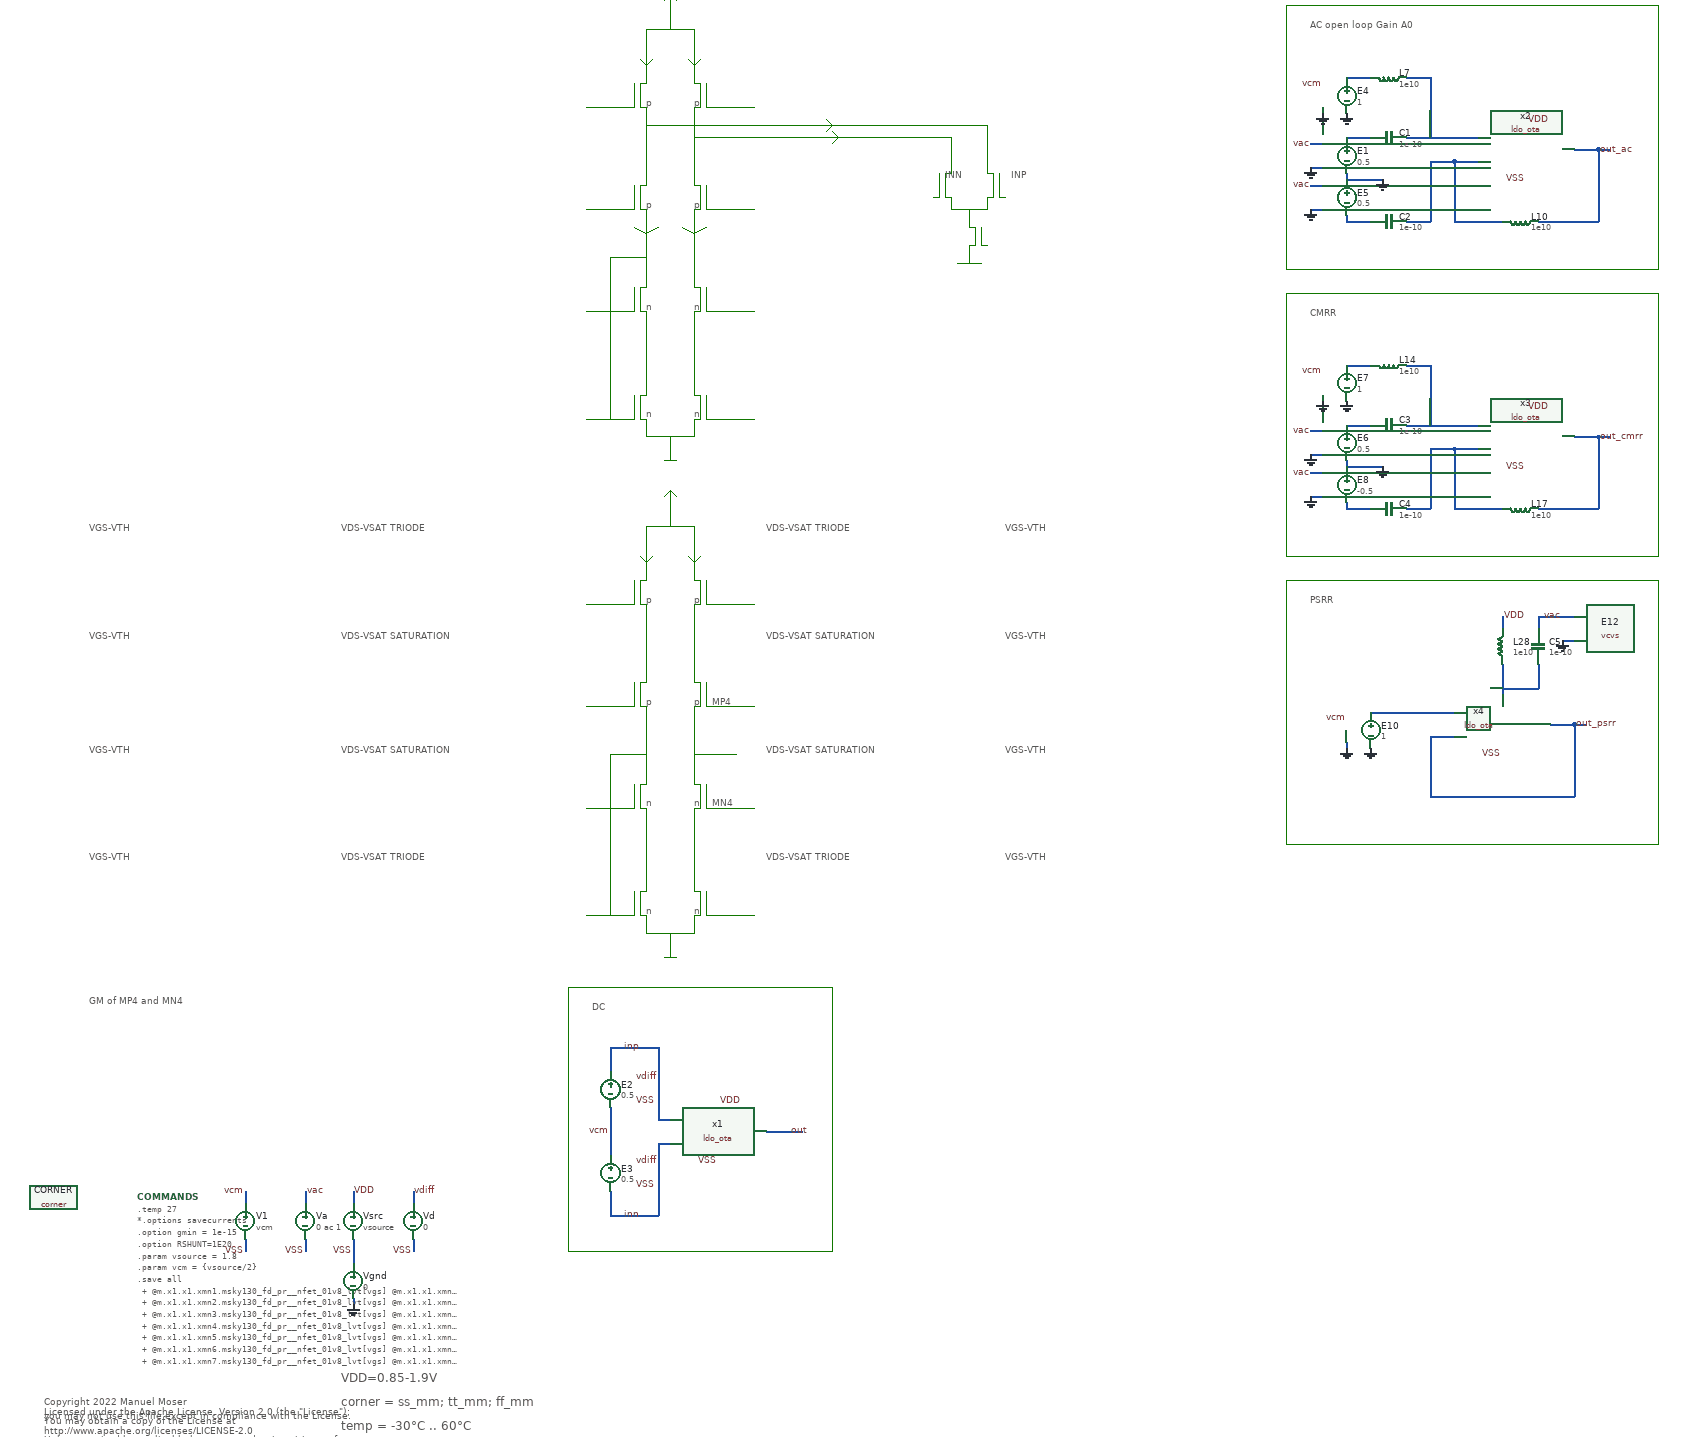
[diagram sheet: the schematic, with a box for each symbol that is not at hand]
v {xschem version=3.1.0 file_version=1.2
}
G {}
K {}
V {}
S {}
E {}
L 4 1010 -1630 1010 -1600 {}
L 4 1000 -1600 1010 -1600 {}
L 4 1000 -1600 1000 -1560 {}
L 4 1000 -1560 1010 -1560 {}
L 4 1010 -1560 1010 -1530 {}
L 4 1090 -1630 1090 -1600 {}
L 4 1090 -1600 1100 -1600 {}
L 4 1100 -1600 1100 -1560 {}
L 4 1090 -1560 1100 -1560 {}
L 4 1090 -1560 1090 -1530 {}
L 4 990 -1600 990 -1560 {}
L 4 1110 -1600 1110 -1560 {}
L 4 1110 -1560 1120 -1560 {}
L 4 980 -1560 990 -1560 {}
L 4 1010 -1460 1010 -1430 {}
L 4 1000 -1430 1010 -1430 {}
L 4 1000 -1430 1000 -1390 {}
L 4 1000 -1390 1010 -1390 {}
L 4 1010 -1390 1010 -1360 {}
L 4 1090 -1460 1090 -1430 {}
L 4 1090 -1430 1100 -1430 {}
L 4 1100 -1430 1100 -1390 {}
L 4 1090 -1390 1100 -1390 {}
L 4 1090 -1390 1090 -1360 {}
L 4 990 -1430 990 -1390 {}
L 4 1110 -1430 1110 -1390 {}
L 4 1110 -1390 1120 -1390 {}
L 4 980 -1390 990 -1390 {}
L 4 1010 -1290 1010 -1260 {}
L 4 1000 -1260 1010 -1260 {}
L 4 1000 -1260 1000 -1220 {}
L 4 1000 -1220 1010 -1220 {}
L 4 1010 -1220 1010 -1190 {}
L 4 1090 -1290 1090 -1260 {}
L 4 1090 -1260 1100 -1260 {}
L 4 1100 -1260 1100 -1220 {}
L 4 1090 -1220 1100 -1220 {}
L 4 1090 -1220 1090 -1190 {}
L 4 990 -1260 990 -1220 {}
L 4 1110 -1260 1110 -1220 {}
L 4 1110 -1220 1120 -1220 {}
L 4 980 -1220 990 -1220 {}
L 4 1010 -1110 1010 -1080 {}
L 4 1000 -1080 1010 -1080 {}
L 4 1000 -1080 1000 -1040 {}
L 4 1000 -1040 1010 -1040 {}
L 4 1010 -1040 1010 -1010 {}
L 4 1090 -1110 1090 -1080 {}
L 4 1090 -1080 1100 -1080 {}
L 4 1100 -1080 1100 -1040 {}
L 4 1090 -1040 1100 -1040 {}
L 4 1090 -1040 1090 -1010 {}
L 4 990 -1080 990 -1040 {}
L 4 1110 -1080 1110 -1040 {}
L 4 1110 -1040 1120 -1040 {}
L 4 980 -1040 990 -1040 {}
L 4 1010 -1190 1010 -1110 {}
L 4 1090 -1190 1090 -1110 {}
L 4 1010 -1360 1010 -1290 {}
L 4 1090 -1360 1090 -1290 {}
L 4 1010 -1530 1010 -1460 {}
L 4 1090 -1520 1090 -1460 {}
L 4 1090 -1530 1090 -1520 {}
L 4 1010 -1690 1090 -1690 {}
L 4 1050 -1750 1050 -1690 {}
L 4 1040 -1740 1050 -1750 {}
L 4 1050 -1750 1060 -1740 {}
L 4 1010 -1010 1090 -1010 {}
L 4 1050 -1010 1050 -970 {}
L 4 1040 -970 1060 -970 {}
L 4 950 -1040 980 -1040 {}
L 4 950 -1310 950 -1040 {}
L 4 950 -1310 1010 -1310 {}
L 4 910 -1220 980 -1220 {}
L 4 910 -1040 950 -1040 {}
L 4 910 -1390 980 -1390 {}
L 4 910 -1560 980 -1560 {}
L 4 1120 -1560 1190 -1560 {}
L 4 1120 -1390 1190 -1390 {}
L 4 1120 -1220 1190 -1220 {}
L 4 1120 -1040 1190 -1040 {}
L 4 1090 -1690 1090 -1630 {}
L 4 1010 -1690 1010 -1630 {}
L 4 1010 -1630 1020 -1640 {}
L 4 1000 -1640 1010 -1630 {}
L 4 1090 -1630 1100 -1640 {}
L 4 1080 -1640 1090 -1630 {}
L 4 1010 -2460 1010 -2430 {}
L 4 1000 -2430 1010 -2430 {}
L 4 1000 -2430 1000 -2390 {}
L 4 1000 -2390 1010 -2390 {}
L 4 1010 -2390 1010 -2360 {}
L 4 1090 -2460 1090 -2430 {}
L 4 1090 -2430 1100 -2430 {}
L 4 1100 -2430 1100 -2390 {}
L 4 1090 -2390 1100 -2390 {}
L 4 1090 -2390 1090 -2360 {}
L 4 990 -2430 990 -2390 {}
L 4 1110 -2430 1110 -2390 {}
L 4 1110 -2390 1120 -2390 {}
L 4 980 -2390 990 -2390 {}
L 4 1010 -2290 1010 -2260 {}
L 4 1000 -2260 1010 -2260 {}
L 4 1000 -2260 1000 -2220 {}
L 4 1000 -2220 1010 -2220 {}
L 4 1010 -2220 1010 -2190 {}
L 4 1090 -2290 1090 -2260 {}
L 4 1090 -2260 1100 -2260 {}
L 4 1100 -2260 1100 -2220 {}
L 4 1090 -2220 1100 -2220 {}
L 4 1090 -2220 1090 -2190 {}
L 4 990 -2260 990 -2220 {}
L 4 1110 -2260 1110 -2220 {}
L 4 1110 -2220 1120 -2220 {}
L 4 980 -2220 990 -2220 {}
L 4 1010 -2120 1010 -2090 {}
L 4 1000 -2090 1010 -2090 {}
L 4 1000 -2090 1000 -2050 {}
L 4 1000 -2050 1010 -2050 {}
L 4 1010 -2050 1010 -2020 {}
L 4 1090 -2120 1090 -2090 {}
L 4 1090 -2090 1100 -2090 {}
L 4 1100 -2090 1100 -2050 {}
L 4 1090 -2050 1100 -2050 {}
L 4 1090 -2050 1090 -2020 {}
L 4 990 -2090 990 -2050 {}
L 4 1110 -2090 1110 -2050 {}
L 4 1110 -2050 1120 -2050 {}
L 4 980 -2050 990 -2050 {}
L 4 1010 -1940 1010 -1910 {}
L 4 1000 -1910 1010 -1910 {}
L 4 1000 -1910 1000 -1870 {}
L 4 1000 -1870 1010 -1870 {}
L 4 1010 -1870 1010 -1840 {}
L 4 1090 -1940 1090 -1910 {}
L 4 1090 -1910 1100 -1910 {}
L 4 1100 -1910 1100 -1870 {}
L 4 1090 -1870 1100 -1870 {}
L 4 1090 -1870 1090 -1840 {}
L 4 990 -1910 990 -1870 {}
L 4 1110 -1910 1110 -1870 {}
L 4 1110 -1870 1120 -1870 {}
L 4 980 -1870 990 -1870 {}
L 4 1010 -2020 1010 -1940 {}
L 4 1090 -2020 1090 -1940 {}
L 4 1010 -2190 1010 -2120 {}
L 4 1090 -2190 1090 -2120 {}
L 4 1010 -2360 1010 -2290 {}
L 4 1090 -2350 1090 -2290 {}
L 4 1090 -2360 1090 -2350 {}
L 4 1010 -2520 1090 -2520 {}
L 4 1050 -2580 1050 -2520 {}
L 4 1040 -2570 1050 -2580 {}
L 4 1050 -2580 1060 -2570 {}
L 4 1010 -1840 1090 -1840 {}
L 4 1050 -1840 1050 -1800 {}
L 4 1040 -1800 1060 -1800 {}
L 4 950 -1870 980 -1870 {}
L 4 950 -2140 950 -1870 {}
L 4 950 -2140 1010 -2140 {}
L 4 910 -2050 980 -2050 {}
L 4 910 -1870 950 -1870 {}
L 4 910 -2220 980 -2220 {}
L 4 910 -2390 980 -2390 {}
L 4 1120 -2390 1190 -2390 {}
L 4 1120 -2220 1190 -2220 {}
L 4 1120 -2050 1190 -2050 {}
L 4 1120 -1870 1190 -1870 {}
L 4 1090 -2520 1090 -2460 {}
L 4 1010 -2520 1010 -2460 {}
L 4 1010 -2460 1020 -2470 {}
L 4 1000 -2470 1010 -2460 {}
L 4 1090 -2460 1100 -2470 {}
L 4 1080 -2470 1090 -2460 {}
L 4 1010 -2180 1030 -2190 {}
L 4 990 -2190 1010 -2180 {}
L 4 1090 -2180 1110 -2190 {}
L 4 1070 -2190 1090 -2180 {}
L 4 1580 -2360 1580 -2320 {}
L 4 1520 -2340 1520 -2320 {}
L 4 1520 -2320 1520 -2280 {}
L 4 1510 -2280 1520 -2280 {}
L 4 1510 -2280 1510 -2240 {}
L 4 1510 -2240 1520 -2240 {}
L 4 1520 -2240 1520 -2220 {}
L 4 1520 -2220 1580 -2220 {}
L 4 1580 -2240 1580 -2220 {}
L 4 1580 -2240 1590 -2240 {}
L 4 1590 -2280 1590 -2240 {}
L 4 1580 -2280 1590 -2280 {}
L 4 1580 -2320 1580 -2280 {}
L 4 1600 -2280 1600 -2240 {}
L 4 1600 -2240 1610 -2240 {}
L 4 1500 -2280 1500 -2240 {}
L 4 1490 -2240 1500 -2240 {}
L 4 1310 -2370 1320 -2360 {}
L 4 1310 -2350 1320 -2360 {}
L 4 1320 -2350 1330 -2340 {}
L 4 1320 -2330 1330 -2340 {}
L 4 1010 -2360 1580 -2360 {}
L 4 1090 -2340 1520 -2340 {}
L 4 1550 -2220 1550 -2190 {}
L 4 1550 -2190 1560 -2190 {}
L 4 1560 -2190 1560 -2160 {}
L 4 1550 -2160 1560 -2160 {}
L 4 1550 -2160 1550 -2130 {}
L 4 1530 -2130 1570 -2130 {}
L 4 1570 -2190 1570 -2160 {}
L 4 1570 -2160 1580 -2160 {}
L 4 1090 -1310 1160 -1310 {}
L 4 2080 -2560 2080 -2120 {}
L 4 2100 -2120 2700 -2120 {}
L 4 2100 -2560 2700 -2560 {}
L 4 2700 -2560 2700 -2120 {}
L 4 2080 -2560 2100 -2560 {}
L 4 2080 -2120 2100 -2120 {}
L 4 880 -920 1320 -920 {}
L 4 880 -920 880 -480 {}
L 4 880 -480 1320 -480 {}
L 4 1320 -920 1320 -480 {}
L 4 2080 -2080 2080 -1640 {}
L 4 2100 -1640 2700 -1640 {}
L 4 2100 -2080 2700 -2080 {}
L 4 2700 -2080 2700 -1640 {}
L 4 2080 -2080 2100 -2080 {}
L 4 2080 -1640 2100 -1640 {}
L 4 2080 -1600 2080 -1160 {}
L 4 2100 -1160 2700 -1160 {}
L 4 2100 -1600 2700 -1600 {}
L 4 2700 -1600 2700 -1160 {}
L 4 2080 -1600 2100 -1600 {}
L 4 2080 -1160 2100 -1160 {}
B 2 500 -1670 890 -1530 {flags=graph
y1=0.13
y2=0.23
ypos1=0
ypos2=2
divy=5
subdivy=1
unity=1
x1=-0.3
x2=0.3
divx=5
subdivx=1


dataset=-1
unitx=1
logx=0
logy=0
color=7
node="\\"MP1 Vds-Vsat;@m.x1.x1.xmp1.msky130_fd_pr__pfet_01v8_lvt[vds] @m.x1.x1.xmp1.msky130_fd_pr__pfet_01v8_lvt[vdsat] -\\""}
B 2 1210 -1670 1590 -1530 {flags=graph
y1=-0.081
y2=0.23
ypos1=0
ypos2=2
divy=5
subdivy=1
unity=1
x1=-0.3
x2=0.3
divx=5
subdivx=1


dataset=-1
unitx=1
logx=0
logy=0
color=7
node="\\"MP2 Vds-Vsat;@m.x1.x1.xmp2.msky130_fd_pr__pfet_01v8_lvt[vds] @m.x1.x1.xmp2.msky130_fd_pr__pfet_01v8_lvt[vdsat] -\\""}
B 2 500 -1490 890 -1350 {flags=graph
y1=1
y2=1.2
ypos1=0
ypos2=2
divy=5
subdivy=1
unity=1
x1=-0.3
x2=0.3
divx=5
subdivx=1


dataset=-1
unitx=1
logx=0
logy=0
color=8
node="\\"MP3 Vds-Vsat;@m.x1.x1.xmp3.msky130_fd_pr__pfet_01v8_lvt[vds] @m.x1.x1.xmp3.msky130_fd_pr__pfet_01v8_lvt[vdsat] -\\""}
B 2 1210 -1490 1590 -1350 {flags=graph
y1=-0.14
y2=1.5
ypos1=0
ypos2=2
divy=5
subdivy=1
unity=1
x1=-0.3
x2=0.3
divx=5
subdivx=1


dataset=-1
unitx=1
logx=0
logy=0
color=8
node="\\"MP4 Vds-Vsat;@m.x1.x1.xmp4.msky130_fd_pr__pfet_01v8_lvt[vds] @m.x1.x1.xmp4.msky130_fd_pr__pfet_01v8_lvt[vdsat] -\\""}
B 2 500 -1300 890 -1160 {flags=graph
y1=0.14
y2=0.39
ypos1=0
ypos2=2
divy=5
subdivy=1
unity=1
x1=-0.3
x2=0.3
divx=5
subdivx=1


dataset=-1
unitx=1
logx=0
logy=0
color=8
node="\\"MN3 Vds-Vsat;@m.x1.x1.xmn3.msky130_fd_pr__nfet_01v8_lvt[vds] @m.x1.x1.xmn3.msky130_fd_pr__nfet_01v8_lvt[vdsat] -\\""}
B 2 1210 -1300 1590 -1160 {flags=graph
y1=-0.069
y2=1.7
ypos1=0
ypos2=2
divy=5
subdivy=1
unity=1
x1=-0.3
x2=0.3
divx=5
subdivx=1


dataset=-1
unitx=1
logx=0
logy=0
color=8
node="\\"MN4 Vds-Vsat;@m.x1.x1.xmn4.msky130_fd_pr__nfet_01v8_lvt[vds] @m.x1.x1.xmn4.msky130_fd_pr__nfet_01v8_lvt[vdsat] -\\""}
B 2 500 -1120 890 -980 {flags=graph
y1=0.015
y2=0.083
ypos1=0
ypos2=2
divy=5
subdivy=1
unity=1
x1=-0.3
x2=0.3
divx=5
subdivx=1


dataset=-1
unitx=1
logx=0
logy=0
color=7
node="\\"MN6 Vds-Vsat;@m.x1.x1.xmn6.msky130_fd_pr__nfet_01v8_lvt[vds] @m.x1.x1.xmn6.msky130_fd_pr__nfet_01v8_lvt[vdsat] -\\""}
B 2 1210 -1120 1590 -980 {flags=graph
y1=-0.055
y2=0.093
ypos1=0
ypos2=2
divy=5
subdivy=1
unity=1
x1=-0.3
x2=0.3
divx=5
subdivx=1


dataset=-1
unitx=1
logx=0
logy=0
color=7
node="\\"MN7 Vds-Vsat;@m.x1.x1.xmn7.msky130_fd_pr__nfet_01v8_lvt[vds] @m.x1.x1.xmn7.msky130_fd_pr__nfet_01v8_lvt[vdsat] -\\""}
B 2 1610 -1670 1990 -1530 {flags=graph
y1=0.032
y2=0.065
ypos1=0
ypos2=2
divy=5
subdivy=1
unity=1
x1=-0.3
x2=0.3
divx=5
subdivx=1


dataset=-1
unitx=1
logx=0
logy=0
color=11
node="\\"MP2 Vov;@m.x1.x1.xmp2.msky130_fd_pr__pfet_01v8_lvt[vgs] @m.x1.x1.xmp2.msky130_fd_pr__pfet_01v8_lvt[vth] -\\""}
B 2 1610 -1490 1990 -1350 {flags=graph
y1=-0.28
y2=0.085
ypos1=0
ypos2=2
divy=5
subdivy=1
unity=1
x1=-0.3
x2=0.3
divx=5
subdivx=1


dataset=-1
unitx=1
logx=0
logy=0
color=11
node="\\"MP4 Vov;@m.x1.x1.xmp4.msky130_fd_pr__pfet_01v8_lvt[vgs] @m.x1.x1.xmp4.msky130_fd_pr__pfet_01v8_lvt[vth] -\\""}
B 2 1610 -1300 1990 -1160 {flags=graph
y1=-0.17
y2=0.013
ypos1=0
ypos2=2
divy=5
subdivy=1
unity=1
x1=-0.3
x2=0.3
divx=5
subdivx=1


dataset=-1
unitx=1
logx=0
logy=0
color=11
node="\\"MN4 Vov;@m.x1.x1.xmn4.msky130_fd_pr__nfet_01v8_lvt[vgs] @m.x1.x1.xmn4.msky130_fd_pr__nfet_01v8_lvt[vth] -\\""}
B 2 1610 -1120 1990 -980 {flags=graph
y1=-0.12
y2=0.00063
ypos1=0
ypos2=2
divy=5
subdivy=1
unity=1
x1=-0.3
x2=0.3
divx=5
subdivx=1


dataset=-1
unitx=1
logx=0
logy=0
color=11
node="\\"MN7 Vov;@m.x1.x1.xmn7.msky130_fd_pr__nfet_01v8_lvt[vgs] @m.x1.x1.xmn7.msky130_fd_pr__nfet_01v8_lvt[vth] -\\""}
B 2 80 -1670 470 -1530 {flags=graph
y1=0.031
y2=0.067
ypos1=0
ypos2=2
divy=5
subdivy=1
unity=1
x1=-0.3
x2=0.3
divx=5
subdivx=1


dataset=-1
unitx=1
logx=0
logy=0
color=11
node="\\"MP1 Vov;@m.x1.x1.xmp1.msky130_fd_pr__pfet_01v8_lvt[vgs] @m.x1.x1.xmp1.msky130_fd_pr__pfet_01v8_lvt[vth] -\\""}
B 2 80 -1490 470 -1350 {flags=graph
y1=-0.28
y2=-0.15
ypos1=0
ypos2=2
divy=5
subdivy=1
unity=1
x1=-0.3
x2=0.3
divx=5
subdivx=1


dataset=-1
unitx=1
logx=0
logy=0
color=11
node="\\"MP3 Vov;@m.x1.x1.xmp3.msky130_fd_pr__pfet_01v8_lvt[vgs] @m.x1.x1.xmp3.msky130_fd_pr__pfet_01v8_lvt[vth] -\\""}
B 2 80 -1300 470 -1160 {flags=graph
y1=-0.17
y2=-0.074
ypos1=0
ypos2=2
divy=5
subdivy=1
unity=1
x1=-0.3
x2=0.3
divx=5
subdivx=1


dataset=-1
unitx=1
logx=0
logy=0
color=11
node="\\"MN3 Vov;@m.x1.x1.xmn3.msky130_fd_pr__nfet_01v8_lvt[vgs] @m.x1.x1.xmn3.msky130_fd_pr__nfet_01v8_lvt[vth] -\\""}
B 2 80 -1120 470 -980 {flags=graph
y1=-0.13
y2=-0.027
ypos1=0
ypos2=2
divy=5
subdivy=1
unity=1
x1=-0.3
x2=0.3
divx=5
subdivx=1


dataset=-1
unitx=1
logx=0
logy=0
color=11
node="\\"MN6 Vov;@m.x1.x1.xmn6.msky130_fd_pr__nfet_01v8_lvt[vgs] @m.x1.x1.xmn6.msky130_fd_pr__nfet_01v8_lvt[vth] -\\""}
B 2 800 -2580 940 -2440 {flags=graph
y1=6.2e-07
y2=1.4e-06
ypos1=0
ypos2=2
divy=5
subdivy=1
unity=1
x1=-0.3
x2=0.3
divx=5
subdivx=1


dataset=-1
unitx=1
logx=0
logy=0
color=12
node=i(@m.x1.x1.xmp1.msky130_fd_pr__pfet_01v8_lvt[id])}
B 2 1140 -2580 1280 -2440 {flags=graph
y1=1.2e-07
y2=1.4e-06
ypos1=0
ypos2=2
divy=5
subdivy=1
unity=1
x1=-0.3
x2=0.3
divx=5
subdivx=1


dataset=-1
unitx=1
logx=0
logy=0
color=12
node=i(@m.x1.x1.xmp2.msky130_fd_pr__pfet_01v8_lvt[id])}
B 2 1140 -2200 1320 -2060 {flags=graph
y1=0
y2=7.8e-07
ypos1=0
ypos2=2
divy=5
subdivy=1
unity=1
x1=-0.3
x2=0.3
divx=5
subdivx=1


dataset=-1
unitx=1
logx=0
logy=0
color=12
node=i(@m.x1.x1.xmp4.msky130_fd_pr__pfet_01v8_lvt[id])}
B 2 760 -2210 940 -2070 {flags=graph
y1=1.2e-07
y2=1.4e-06
ypos1=0
ypos2=2
divy=5
subdivy=1
unity=1
x1=-0.3
x2=0.3
divx=5
subdivx=1


dataset=-1
unitx=1
logx=0
logy=0
color=12
node=i(@m.x1.x1.xmp3.msky130_fd_pr__pfet_01v8_lvt[id])}
B 2 1340 -2320 1470 -2180 {flags=graph
y1=1.7e-11
y2=1.1e-06
ypos1=0
ypos2=2
divy=5
subdivy=1
unity=1
x1=-0.3
x2=0.3
divx=5
subdivx=1


dataset=-1
unitx=1
logx=0
logy=0
color=12
node=i(@m.x1.x1.xmn2.msky130_fd_pr__nfet_01v8_lvt[id])}
B 2 1330 -2520 1470 -2380 {flags=graph
y1=1.7e-11
y2=1.1e-06
ypos1=0
ypos2=2
divy=5
subdivy=1
unity=1
x1=-0.3
x2=0.3
divx=5
subdivx=1


dataset=-1
unitx=1
logx=0
logy=0
color=12
node=i(@m.x1.x1.xmn1.msky130_fd_pr__nfet_01v8_lvt[id])}
B 2 80 -880 470 -720 {flags=graph
y1=1.3e-06
y2=2.5e-05
ypos1=0
ypos2=2
divy=5
subdivy=1
unity=1
x1=-0.3
x2=0.3
divx=5
subdivx=1


dataset=-1
unitx=1
logx=0
logy=0

color="7 4"
node="\\"MP4 gm;@m.x1.x1.xmp4.msky130_fd_pr__pfet_01v8_lvt[gm]\\"
\\"MN4 gm;@m.x1.x1.xmn4.msky130_fd_pr__nfet_01v8_lvt[gm]\\""}
B 2 3380 -2560 3960 -2160 {flags=graph,unlocked
y1=-180
y2=0
ypos1=0
ypos2=2
divy=5
subdivy=1
unity=1
x1=2
x2=7
divx=5
subdivx=8
node="\\"Phase (deg);ph(out_ac)\\""
color=4
dataset=-1
unitx=1
logx=1
logy=0
}
B 2 1410 -880 1990 -480 {flags=graph
y1=0.0081
y2=1.8
ypos1=0
ypos2=2
divy=5
subdivy=1
unity=1
x1=-0.3
x2=0.3
divx=5
subdivx=1
node=out
color=4
dataset=-1
unitx=1
logx=0
logy=0
}
B 2 2760 -2560 3340 -2160 {flags=graph,unlocked
y1=-17
y2=69
ypos1=0
ypos2=2
divy=5
subdivy=1
unity=1
x1=2
x2=7
divx=5
subdivx=8
node="\\"Open Loop Gain A0 (dB);out_ac db20()\\""
color=4
dataset=-1
unitx=1
logx=1
logy=0
}
B 2 2760 -2080 3340 -1680 {flags=graph,unlocked
y1=40.158
y2=127.158
ypos1=0
ypos2=2
divy=5
subdivy=1
unity=1
x1=2
x2=7
divx=5
subdivx=8
node="\\"CMRR (dB) A0/Acm;out_ac db20() out_cmrr db20() -\\""
color=4
dataset=-1
unitx=1
logx=1
logy=0
}
B 2 2760 -1600 3340 -1200 {flags=graph,unlocked
y1=0.61
y2=110
ypos1=0
ypos2=2
divy=5
subdivy=1
unity=1
x1=2
x2=7
divx=5
subdivx=8
node="\\"PSRR (dB);0 out_psrr db20() -\\""
color=4
dataset=-1
unitx=1
logx=1
logy=0
}
T {   Copyright 2022 Manuel Moser

   Licensed under the Apache License, Version 2.0 (the "License");
   you may not use this file except in compliance with the License.
   You may obtain a copy of the License at

       http://www.apache.org/licenses/LICENSE-2.0

   Unless required by applicable law or agreed to in writing, software
   distributed under the License is distributed on an "AS IS" BASIS,
   WITHOUT WARRANTIES OR CONDITIONS OF ANY KIND, either express or implied.
   See the License for the specific language governing permissions and
   limitations under the License.} 0 -240 0 0 0.2 0.2 {}
T {p} 1010 -1580 0 0 0.2 0.2 {}
T {p} 1090 -1580 0 0 0.2 0.2 {}
T {p} 1010 -1410 0 0 0.2 0.2 {}
T {p} 1090 -1410 0 0 0.2 0.2 {}
T {n} 1010 -1240 0 0 0.2 0.2 {}
T {n} 1090 -1240 0 0 0.2 0.2 {}
T {n} 1010 -1060 0 0 0.2 0.2 {}
T {n} 1090 -1060 0 0 0.2 0.2 {}
T {VDS-VSAT SATURATION} 500 -1520 0 0 0.4 0.4 {}
T {VDS-VSAT SATURATION} 1210 -1520 0 0 0.4 0.4 {}
T {VDS-VSAT TRIODE} 500 -1700 0 0 0.4 0.4 {}
T {VDS-VSAT TRIODE} 1210 -1700 0 0 0.4 0.4 {}
T {VDS-VSAT TRIODE} 500 -1150 0 0 0.4 0.4 {}
T {VDS-VSAT TRIODE} 1210 -1150 0 0 0.4 0.4 {}
T {VDS-VSAT SATURATION} 500 -1330 0 0 0.4 0.4 {}
T {VDS-VSAT SATURATION} 1210 -1330 0 0 0.4 0.4 {}
T {VGS-VTH} 1610 -1520 0 0 0.4 0.4 {}
T {VGS-VTH} 1610 -1700 0 0 0.4 0.4 {}
T {VGS-VTH} 1610 -1150 0 0 0.4 0.4 {}
T {VGS-VTH} 1610 -1330 0 0 0.4 0.4 {}
T {VGS-VTH} 80 -1520 0 0 0.4 0.4 {}
T {VGS-VTH} 80 -1700 0 0 0.4 0.4 {}
T {VGS-VTH} 80 -1150 0 0 0.4 0.4 {}
T {VGS-VTH} 80 -1330 0 0 0.4 0.4 {}
T {p} 1010 -2410 0 0 0.2 0.2 {}
T {p} 1090 -2410 0 0 0.2 0.2 {}
T {p} 1010 -2240 0 0 0.2 0.2 {}
T {p} 1090 -2240 0 0 0.2 0.2 {}
T {n} 1010 -2070 0 0 0.2 0.2 {}
T {n} 1090 -2070 0 0 0.2 0.2 {}
T {n} 1010 -1890 0 0 0.2 0.2 {}
T {n} 1090 -1890 0 0 0.2 0.2 {}
T {INP} 1620 -2290 2 0 0.4 0.4 {}
T {INN} 1510 -2290 2 0 0.4 0.4 {}
T {MP4} 1120 -1410 0 0 0.2 0.2 {}
T {MN4} 1120 -1240 0 0 0.2 0.2 {}
T {GM of MP4 and MN4} 80 -910 0 0 0.4 0.4 {}
T {VDD=0.85-1.9V} 500 -280 0 0 0.6 0.6 {}
T {corner = ss_mm; tt_mm; ff_mm} 500 -240 0 0 0.6 0.6 {}
T {temp = -30°C .. 60°C} 500 -200 0 0 0.6 0.6 {}
T {AC open loop Gain A0} 2120 -2540 0 0 0.4 0.4 {}
T {DC} 920 -900 0 0 0.4 0.4 {}
T {CMRR} 2120 -2060 0 0 0.4 0.4 {}
T {PSRR} 2120 -1580 0 0 0.4 0.4 {}
N 1030 -700 1050 -700 {
lab=inp}
N 1030 -660 1050 -660 {
lab=inn}
N 520 -500 520 -480 {
lab=VSS}
N 340 -500 340 -480 {
lab=VSS}
N 520 -580 520 -560 {
lab=VDD}
N 1210 -680 1250 -680 {
lab=out}
N 1250 -680 1270 -680 {
lab=out}
N 620 -500 620 -480 {
lab=VSS}
N 620 -580 620 -560 {
lab=vdiff}
N 950 -720 950 -680 {
lab=vcm}
N 950 -580 950 -540 {
lab=inn}
N 950 -540 1030 -540 {
lab=inn}
N 1030 -660 1030 -540 {
lab=inn}
N 950 -820 950 -780 {
lab=inp}
N 950 -820 1030 -820 {
lab=inp}
N 1030 -820 1030 -700 {
lab=inp}
N 950 -680 950 -640 {
lab=vcm}
N 520 -480 520 -460 {
lab=VSS}
N 520 -400 520 -390 {
lab=GND}
N 2380 -2340 2400 -2340 {
lab=#net1}
N 2560 -2320 2600 -2320 {
lab=out_ac}
N 2600 -2320 2620 -2320 {
lab=out_ac}
N 440 -500 440 -480 {
lab=VSS}
N 440 -580 440 -560 {
lab=vac}
N 2120 -2330 2140 -2330 {
lab=vac}
N 2120 -2290 2140 -2290 {
lab=GND}
N 2340 -2340 2380 -2340 {
lab=#net1}
N 2180 -2340 2220 -2340 {
lab=#net2}
N 2280 -2340 2340 -2340 {
lab=#net1}
N 2140 -2390 2140 -2380 {
lab=GND}
N 340 -580 340 -560 {
lab=vcm}
N 2180 -2440 2220 -2440 {
lab=#net3}
N 2280 -2440 2320 -2440 {
lab=#net1}
N 2320 -2440 2320 -2340 {
lab=#net1}
N 2360 -2200 2440 -2200 {
lab=#net4}
N 2360 -2300 2360 -2200 {
lab=#net4}
N 2360 -2300 2400 -2300 {
lab=#net4}
N 2500 -2200 2600 -2200 {
lab=out_ac}
N 2600 -2320 2600 -2200 {
lab=out_ac}
N 2120 -2220 2140 -2220 {
lab=GND}
N 2180 -2280 2180 -2270 {
lab=GND}
N 2120 -2260 2140 -2260 {
lab=vac}
N 2180 -2210 2180 -2200 {
lab=#net5}
N 2180 -2200 2220 -2200 {
lab=#net5}
N 2280 -2200 2300 -2200 {
lab=#net4}
N 2300 -2200 2320 -2200 {
lab=#net4}
N 2320 -2300 2320 -2200 {
lab=#net4}
N 2320 -2300 2360 -2300 {
lab=#net4}
N 2180 -2270 2240 -2270 {
lab=GND}
N 2380 -1860 2400 -1860 {
lab=#net6}
N 2560 -1840 2600 -1840 {
lab=out_cmrr}
N 2600 -1840 2620 -1840 {
lab=out_cmrr}
N 2120 -1850 2140 -1850 {
lab=vac}
N 2120 -1810 2140 -1810 {
lab=GND}
N 2340 -1860 2380 -1860 {
lab=#net6}
N 2180 -1860 2220 -1860 {
lab=#net7}
N 2280 -1860 2340 -1860 {
lab=#net6}
N 2140 -1910 2140 -1900 {
lab=GND}
N 2180 -1960 2220 -1960 {
lab=#net8}
N 2280 -1960 2320 -1960 {
lab=#net6}
N 2320 -1960 2320 -1860 {
lab=#net6}
N 2360 -1720 2440 -1720 {
lab=#net9}
N 2360 -1820 2360 -1720 {
lab=#net9}
N 2360 -1820 2400 -1820 {
lab=#net9}
N 2500 -1720 2600 -1720 {
lab=out_cmrr}
N 2600 -1840 2600 -1720 {
lab=out_cmrr}
N 2120 -1740 2140 -1740 {
lab=GND}
N 2180 -1800 2180 -1790 {
lab=GND}
N 2120 -1780 2140 -1780 {
lab=vac}
N 2180 -1730 2180 -1720 {
lab=#net10}
N 2180 -1720 2220 -1720 {
lab=#net10}
N 2280 -1720 2300 -1720 {
lab=#net9}
N 2300 -1720 2320 -1720 {
lab=#net9}
N 2320 -1820 2320 -1720 {
lab=#net9}
N 2320 -1820 2360 -1820 {
lab=#net9}
N 2180 -1790 2240 -1790 {
lab=GND}
N 2340 -1380 2360 -1380 {
lab=#net11}
N 2520 -1360 2560 -1360 {
lab=out_psrr}
N 2560 -1360 2580 -1360 {
lab=out_psrr}
N 2300 -1380 2340 -1380 {
lab=#net11}
N 2180 -1330 2180 -1320 {
lab=GND}
N 2220 -1380 2260 -1380 {
lab=#net11}
N 2320 -1240 2400 -1240 {
lab=out_psrr}
N 2320 -1340 2320 -1240 {
lab=out_psrr}
N 2320 -1340 2360 -1340 {
lab=out_psrr}
N 2460 -1240 2560 -1240 {
lab=out_psrr}
N 2560 -1360 2560 -1240 {
lab=out_psrr}
N 2440 -1540 2440 -1520 {
lab=VDD}
N 2540 -1540 2560 -1540 {
lab=vac}
N 2540 -1500 2560 -1500 {
lab=GND}
N 2440 -1460 2440 -1410 {
lab=#net12}
N 2500 -1540 2540 -1540 {
lab=vac}
N 2500 -1540 2500 -1520 {
lab=vac}
N 2500 -1460 2500 -1420 {
lab=#net12}
N 2440 -1420 2500 -1420 {
lab=#net12}
N 2280 -1380 2300 -1380 {
lab=#net11}
N 2260 -1380 2280 -1380 {
lab=#net11}
N 2400 -1240 2460 -1240 {
lab=out_psrr}
C {devices/title.sym} 170 -40 0 0 {name=l1 author="Manuel Moser"}
C {devices/simulator_commands.sym} 160 -570 0 0 {name=COMMANDS
simulator=ngspice
only_toplevel=false 
value="
.temp 27
*.options savecurrents
.option gmin = 1e-15
.option RSHUNT=1E20

.param vsource = 1.8
.param vcm = \{vsource/2\}


.save all
 + @m.x1.x1.xmn1.msky130_fd_pr__nfet_01v8_lvt[vgs] @m.x1.x1.xmn1.msky130_fd_pr__nfet_01v8_lvt[vth] @m.x1.x1.xmn1.msky130_fd_pr__nfet_01v8_lvt[vds] @m.x1.x1.xmn1.msky130_fd_pr__nfet_01v8_lvt[vdsat] @m.x1.x1.xmn1.msky130_fd_pr__nfet_01v8_lvt[id] @m.x1.x1.xmn1.msky130_fd_pr__nfet_01v8_lvt[gm]
 + @m.x1.x1.xmn2.msky130_fd_pr__nfet_01v8_lvt[vgs] @m.x1.x1.xmn2.msky130_fd_pr__nfet_01v8_lvt[vth] @m.x1.x1.xmn2.msky130_fd_pr__nfet_01v8_lvt[vds] @m.x1.x1.xmn2.msky130_fd_pr__nfet_01v8_lvt[vdsat] @m.x1.x1.xmn2.msky130_fd_pr__nfet_01v8_lvt[id] @m.x1.x1.xmn2.msky130_fd_pr__nfet_01v8_lvt[gm]
 + @m.x1.x1.xmn3.msky130_fd_pr__nfet_01v8_lvt[vgs] @m.x1.x1.xmn3.msky130_fd_pr__nfet_01v8_lvt[vth] @m.x1.x1.xmn3.msky130_fd_pr__nfet_01v8_lvt[vds] @m.x1.x1.xmn3.msky130_fd_pr__nfet_01v8_lvt[vdsat] @m.x1.x1.xmn3.msky130_fd_pr__nfet_01v8_lvt[id] @m.x1.x1.xmn3.msky130_fd_pr__nfet_01v8_lvt[gm]
 + @m.x1.x1.xmn4.msky130_fd_pr__nfet_01v8_lvt[vgs] @m.x1.x1.xmn4.msky130_fd_pr__nfet_01v8_lvt[vth] @m.x1.x1.xmn4.msky130_fd_pr__nfet_01v8_lvt[vds] @m.x1.x1.xmn4.msky130_fd_pr__nfet_01v8_lvt[vdsat] @m.x1.x1.xmn4.msky130_fd_pr__nfet_01v8_lvt[id] @m.x1.x1.xmn4.msky130_fd_pr__nfet_01v8_lvt[gm]
 + @m.x1.x1.xmn5.msky130_fd_pr__nfet_01v8_lvt[vgs] @m.x1.x1.xmn5.msky130_fd_pr__nfet_01v8_lvt[vth] @m.x1.x1.xmn5.msky130_fd_pr__nfet_01v8_lvt[vds] @m.x1.x1.xmn5.msky130_fd_pr__nfet_01v8_lvt[vdsat] @m.x1.x1.xmn5.msky130_fd_pr__nfet_01v8_lvt[id] @m.x1.x1.xmn5.msky130_fd_pr__nfet_01v8_lvt[gm]
 + @m.x1.x1.xmn6.msky130_fd_pr__nfet_01v8_lvt[vgs] @m.x1.x1.xmn6.msky130_fd_pr__nfet_01v8_lvt[vth] @m.x1.x1.xmn6.msky130_fd_pr__nfet_01v8_lvt[vds] @m.x1.x1.xmn6.msky130_fd_pr__nfet_01v8_lvt[vdsat] @m.x1.x1.xmn6.msky130_fd_pr__nfet_01v8_lvt[id] @m.x1.x1.xmn6.msky130_fd_pr__nfet_01v8_lvt[gm]
 + @m.x1.x1.xmn7.msky130_fd_pr__nfet_01v8_lvt[vgs] @m.x1.x1.xmn7.msky130_fd_pr__nfet_01v8_lvt[vth] @m.x1.x1.xmn7.msky130_fd_pr__nfet_01v8_lvt[vds] @m.x1.x1.xmn7.msky130_fd_pr__nfet_01v8_lvt[vdsat] @m.x1.x1.xmn7.msky130_fd_pr__nfet_01v8_lvt[id] @m.x1.x1.xmn7.msky130_fd_pr__nfet_01v8_lvt[gm]
 + @m.x1.x1.xmp1.msky130_fd_pr__pfet_01v8_lvt[vgs] @m.x1.x1.xmp1.msky130_fd_pr__pfet_01v8_lvt[vth] @m.x1.x1.xmp1.msky130_fd_pr__pfet_01v8_lvt[vds] @m.x1.x1.xmp1.msky130_fd_pr__pfet_01v8_lvt[vdsat] @m.x1.x1.xmp1.msky130_fd_pr__pfet_01v8_lvt[id] @m.x1.x1.xmp1.msky130_fd_pr__pfet_01v8_lvt[gm]
 + @m.x1.x1.xmp2.msky130_fd_pr__pfet_01v8_lvt[vgs] @m.x1.x1.xmp2.msky130_fd_pr__pfet_01v8_lvt[vth] @m.x1.x1.xmp2.msky130_fd_pr__pfet_01v8_lvt[vds] @m.x1.x1.xmp2.msky130_fd_pr__pfet_01v8_lvt[vdsat] @m.x1.x1.xmp2.msky130_fd_pr__pfet_01v8_lvt[id] @m.x1.x1.xmp2.msky130_fd_pr__pfet_01v8_lvt[gm]
 + @m.x1.x1.xmp3.msky130_fd_pr__pfet_01v8_lvt[vgs] @m.x1.x1.xmp3.msky130_fd_pr__pfet_01v8_lvt[vth] @m.x1.x1.xmp3.msky130_fd_pr__pfet_01v8_lvt[vds] @m.x1.x1.xmp3.msky130_fd_pr__pfet_01v8_lvt[vdsat] @m.x1.x1.xmp3.msky130_fd_pr__pfet_01v8_lvt[id] @m.x1.x1.xmp3.msky130_fd_pr__pfet_01v8_lvt[gm]
 + @m.x1.x1.xmp4.msky130_fd_pr__pfet_01v8_lvt[vgs] @m.x1.x1.xmp4.msky130_fd_pr__pfet_01v8_lvt[vth] @m.x1.x1.xmp4.msky130_fd_pr__pfet_01v8_lvt[vds] @m.x1.x1.xmp4.msky130_fd_pr__pfet_01v8_lvt[vdsat] @m.x1.x1.xmp4.msky130_fd_pr__pfet_01v8_lvt[id] @m.x1.x1.xmp4.msky130_fd_pr__pfet_01v8_lvt[gm]

.control
set num_threads = 12
write results.raw
*write results_ac.raw
set appendwrite

repeat 10
 reset
 dc vd -300m 300m 0.1m temp -30 60 90
 
write results.raw out x1.bias1 x1.bias2 x1.bias3 x1.bias4
 + @m.x1.x1.xmn1.msky130_fd_pr__nfet_01v8_lvt[vgs] @m.x1.x1.xmn1.msky130_fd_pr__nfet_01v8_lvt[vth] @m.x1.x1.xmn1.msky130_fd_pr__nfet_01v8_lvt[vds] @m.x1.x1.xmn1.msky130_fd_pr__nfet_01v8_lvt[vdsat] @m.x1.x1.xmn1.msky130_fd_pr__nfet_01v8_lvt[id] @m.x1.x1.xmn1.msky130_fd_pr__nfet_01v8_lvt[gm]
 + @m.x1.x1.xmn2.msky130_fd_pr__nfet_01v8_lvt[vgs] @m.x1.x1.xmn2.msky130_fd_pr__nfet_01v8_lvt[vth] @m.x1.x1.xmn2.msky130_fd_pr__nfet_01v8_lvt[vds] @m.x1.x1.xmn2.msky130_fd_pr__nfet_01v8_lvt[vdsat] @m.x1.x1.xmn2.msky130_fd_pr__nfet_01v8_lvt[id] @m.x1.x1.xmn2.msky130_fd_pr__nfet_01v8_lvt[gm]
 + @m.x1.x1.xmn3.msky130_fd_pr__nfet_01v8_lvt[vgs] @m.x1.x1.xmn3.msky130_fd_pr__nfet_01v8_lvt[vth] @m.x1.x1.xmn3.msky130_fd_pr__nfet_01v8_lvt[vds] @m.x1.x1.xmn3.msky130_fd_pr__nfet_01v8_lvt[vdsat] @m.x1.x1.xmn3.msky130_fd_pr__nfet_01v8_lvt[id] @m.x1.x1.xmn3.msky130_fd_pr__nfet_01v8_lvt[gm]
 + @m.x1.x1.xmn4.msky130_fd_pr__nfet_01v8_lvt[vgs] @m.x1.x1.xmn4.msky130_fd_pr__nfet_01v8_lvt[vth] @m.x1.x1.xmn4.msky130_fd_pr__nfet_01v8_lvt[vds] @m.x1.x1.xmn4.msky130_fd_pr__nfet_01v8_lvt[vdsat] @m.x1.x1.xmn4.msky130_fd_pr__nfet_01v8_lvt[id] @m.x1.x1.xmn4.msky130_fd_pr__nfet_01v8_lvt[gm]
 + @m.x1.x1.xmn5.msky130_fd_pr__nfet_01v8_lvt[vgs] @m.x1.x1.xmn5.msky130_fd_pr__nfet_01v8_lvt[vth] @m.x1.x1.xmn5.msky130_fd_pr__nfet_01v8_lvt[vds] @m.x1.x1.xmn5.msky130_fd_pr__nfet_01v8_lvt[vdsat] @m.x1.x1.xmn5.msky130_fd_pr__nfet_01v8_lvt[id] @m.x1.x1.xmn5.msky130_fd_pr__nfet_01v8_lvt[gm]
 + @m.x1.x1.xmn6.msky130_fd_pr__nfet_01v8_lvt[vgs] @m.x1.x1.xmn6.msky130_fd_pr__nfet_01v8_lvt[vth] @m.x1.x1.xmn6.msky130_fd_pr__nfet_01v8_lvt[vds] @m.x1.x1.xmn6.msky130_fd_pr__nfet_01v8_lvt[vdsat] @m.x1.x1.xmn6.msky130_fd_pr__nfet_01v8_lvt[id] @m.x1.x1.xmn6.msky130_fd_pr__nfet_01v8_lvt[gm]
 + @m.x1.x1.xmn7.msky130_fd_pr__nfet_01v8_lvt[vgs] @m.x1.x1.xmn7.msky130_fd_pr__nfet_01v8_lvt[vth] @m.x1.x1.xmn7.msky130_fd_pr__nfet_01v8_lvt[vds] @m.x1.x1.xmn7.msky130_fd_pr__nfet_01v8_lvt[vdsat] @m.x1.x1.xmn7.msky130_fd_pr__nfet_01v8_lvt[id] @m.x1.x1.xmn7.msky130_fd_pr__nfet_01v8_lvt[gm]
 + @m.x1.x1.xmp1.msky130_fd_pr__pfet_01v8_lvt[vgs] @m.x1.x1.xmp1.msky130_fd_pr__pfet_01v8_lvt[vth] @m.x1.x1.xmp1.msky130_fd_pr__pfet_01v8_lvt[vds] @m.x1.x1.xmp1.msky130_fd_pr__pfet_01v8_lvt[vdsat] @m.x1.x1.xmp1.msky130_fd_pr__pfet_01v8_lvt[id] @m.x1.x1.xmp1.msky130_fd_pr__pfet_01v8_lvt[gm]
 + @m.x1.x1.xmp2.msky130_fd_pr__pfet_01v8_lvt[vgs] @m.x1.x1.xmp2.msky130_fd_pr__pfet_01v8_lvt[vth] @m.x1.x1.xmp2.msky130_fd_pr__pfet_01v8_lvt[vds] @m.x1.x1.xmp2.msky130_fd_pr__pfet_01v8_lvt[vdsat] @m.x1.x1.xmp2.msky130_fd_pr__pfet_01v8_lvt[id] @m.x1.x1.xmp2.msky130_fd_pr__pfet_01v8_lvt[gm]
 + @m.x1.x1.xmp3.msky130_fd_pr__pfet_01v8_lvt[vgs] @m.x1.x1.xmp3.msky130_fd_pr__pfet_01v8_lvt[vth] @m.x1.x1.xmp3.msky130_fd_pr__pfet_01v8_lvt[vds] @m.x1.x1.xmp3.msky130_fd_pr__pfet_01v8_lvt[vdsat] @m.x1.x1.xmp3.msky130_fd_pr__pfet_01v8_lvt[id] @m.x1.x1.xmp3.msky130_fd_pr__pfet_01v8_lvt[gm]
 + @m.x1.x1.xmp4.msky130_fd_pr__pfet_01v8_lvt[vgs] @m.x1.x1.xmp4.msky130_fd_pr__pfet_01v8_lvt[vth] @m.x1.x1.xmp4.msky130_fd_pr__pfet_01v8_lvt[vds] @m.x1.x1.xmp4.msky130_fd_pr__pfet_01v8_lvt[vdsat] @m.x1.x1.xmp4.msky130_fd_pr__pfet_01v8_lvt[id] @m.x1.x1.xmp4.msky130_fd_pr__pfet_01v8_lvt[gm]


 ac dec 10 100 10meg
 write results.raw out_ac out_cmrr out_psrr


end

.endc

"}
C {sky130_fd_pr/corner.sym} 20 -570 0 0 {name=CORNER only_toplevel=false corner=tt_mm}
C {ldo_ota.sym} 1130 -680 0 0 {name=x1}
C {devices/vsource.sym} 340 -530 0 0 {name=V1 value=vcm}
C {devices/vsource.sym} 620 -530 0 0 {name=Vd value="0"}
C {devices/vsource.sym} 520 -530 0 0 {name=Vsrc value=vsource}
C {devices/lab_wire.sym} 520 -580 0 1 {name=p9 sig_type=std_logic lab=VDD}
C {devices/lab_wire.sym} 520 -480 2 1 {name=p1 sig_type=std_logic lab=VSS}
C {devices/lab_wire.sym} 1130 -730 0 1 {name=p2 sig_type=std_logic lab=VDD}
C {devices/lab_wire.sym} 1130 -630 2 1 {name=p3 sig_type=std_logic lab=VSS}
C {devices/lab_wire.sym} 340 -480 2 1 {name=p4 sig_type=std_logic lab=VSS}
C {devices/lab_wire.sym} 1250 -680 0 1 {name=p5 sig_type=std_logic lab=out}
C {devices/noconn.sym} 1270 -680 0 1 {name=l2}
C {devices/lab_wire.sym} 620 -480 2 1 {name=p6 sig_type=std_logic lab=VSS}
C {devices/lab_wire.sym} 620 -580 0 1 {name=p7 sig_type=std_logic lab=vdiff}
C {devices/vcvs.sym} 950 -750 0 1 {name=E2 value=0.5}
C {devices/vcvs.sym} 950 -610 0 1 {name=E3 value=0.5}
C {devices/lab_wire.sym} 990 -770 0 1 {name=p8 sig_type=std_logic lab=vdiff}
C {devices/lab_wire.sym} 990 -730 0 1 {name=p10 sig_type=std_logic lab=VSS}
C {devices/lab_wire.sym} 990 -590 2 0 {name=p11 sig_type=std_logic lab=VSS}
C {devices/lab_wire.sym} 990 -630 2 0 {name=p12 sig_type=std_logic lab=vdiff}
C {devices/lab_wire.sym} 970 -820 0 1 {name=p14 sig_type=std_logic lab=inp}
C {devices/lab_wire.sym} 970 -540 0 1 {name=p15 sig_type=std_logic lab=inn}
C {devices/vsource.sym} 520 -430 0 0 {name=Vgnd value=0}
C {devices/gnd.sym} 520 -390 0 0 {name=l3 lab=GND}
C {ldo_ota.sym} 2480 -2320 0 0 {name=x2}
C {devices/lab_wire.sym} 2480 -2370 0 1 {name=p13 sig_type=std_logic lab=VDD}
C {devices/lab_wire.sym} 2480 -2270 2 1 {name=p16 sig_type=std_logic lab=VSS}
C {devices/lab_wire.sym} 2600 -2320 0 1 {name=p18 sig_type=std_logic lab=out_ac}
C {devices/noconn.sym} 2620 -2320 0 1 {name=l4}
C {devices/launcher.sym} 1470 -900 0 0 {name=h2
descr="load dc results.raw" 
tclcommand="xschem raw_read $netlist_dir/results.raw dc"
}
C {devices/launcher.sym} 2820 -2580 0 0 {name=h3
descr="load ac results.raw" 
tclcommand="xschem raw_read $netlist_dir/results.raw ac"
}
C {devices/vsource.sym} 440 -530 0 0 {name=Va value="0 ac 1"}
C {devices/lab_wire.sym} 440 -480 2 1 {name=Vac1 sig_type=std_logic lab=VSS
value="0 ac 1"}
C {devices/lab_wire.sym} 440 -580 0 1 {name=Vac2 sig_type=std_logic lab=vac
value="0 ac 1"}
C {devices/vcvs.sym} 2180 -2310 0 0 {name=E1 value=0.5}
C {devices/lab_wire.sym} 2120 -2330 0 0 {name=Vac3 sig_type=std_logic lab=vac
value="0 ac 1"}
C {devices/gnd.sym} 2120 -2290 0 0 {name=l5 lab=GND}
C {devices/capa.sym} 2250 -2340 3 1 {name=C1
m=1
value=1e-10
footprint=1206
device="ceramic capacitor"}
C {devices/ind.sym} 2250 -2440 1 0 {name=L7
m=1
value=1e10
footprint=1206
device=inductor}
C {devices/vcvs.sym} 2180 -2410 0 0 {name=E4 value=1}
C {devices/gnd.sym} 2180 -2380 0 0 {name=l8 lab=GND}
C {devices/gnd.sym} 2140 -2380 0 0 {name=l9 lab=GND}
C {devices/lab_wire.sym} 340 -580 0 0 {name=p17 sig_type=std_logic lab=vcm}
C {devices/lab_wire.sym} 950 -680 0 0 {name=p19 sig_type=std_logic lab=vcm}
C {devices/lab_wire.sym} 2140 -2430 0 0 {name=p20 sig_type=std_logic lab=vcm}
C {devices/ind.sym} 2470 -2200 1 0 {name=L10
m=1
value=1e10
footprint=1206
device=inductor}
C {devices/vcvs.sym} 2180 -2240 0 0 {name=E5 value=0.5}
C {devices/gnd.sym} 2120 -2220 0 0 {name=l6 lab=GND}
C {devices/lab_wire.sym} 2120 -2260 0 0 {name=Vac4 sig_type=std_logic lab=vac
value="0 ac 1"}
C {devices/capa.sym} 2250 -2200 3 1 {name=C2
m=1
value=1e-10
footprint=1206
device="ceramic capacitor"}
C {devices/gnd.sym} 2240 -2270 0 0 {name=l11 lab=GND}
C {ldo_ota.sym} 2480 -1840 0 0 {name=x3}
C {devices/lab_wire.sym} 2480 -1890 0 1 {name=p21 sig_type=std_logic lab=VDD}
C {devices/lab_wire.sym} 2480 -1790 2 1 {name=p22 sig_type=std_logic lab=VSS}
C {devices/lab_wire.sym} 2600 -1840 0 1 {name=p23 sig_type=std_logic lab=out_cmrr}
C {devices/noconn.sym} 2620 -1840 0 1 {name=l12}
C {devices/vcvs.sym} 2180 -1830 0 0 {name=E6 value=0.5}
C {devices/lab_wire.sym} 2120 -1850 0 0 {name=Vac5 sig_type=std_logic lab=vac
value="0 ac 1"}
C {devices/gnd.sym} 2120 -1810 0 0 {name=l13 lab=GND}
C {devices/capa.sym} 2250 -1860 3 1 {name=C3
m=1
value=1e-10
footprint=1206
device="ceramic capacitor"}
C {devices/ind.sym} 2250 -1960 1 0 {name=L14
m=1
value=1e10
footprint=1206
device=inductor}
C {devices/vcvs.sym} 2180 -1930 0 0 {name=E7 value=1}
C {devices/gnd.sym} 2180 -1900 0 0 {name=l15 lab=GND}
C {devices/gnd.sym} 2140 -1900 0 0 {name=l16 lab=GND}
C {devices/lab_wire.sym} 2140 -1950 0 0 {name=p24 sig_type=std_logic lab=vcm}
C {devices/ind.sym} 2470 -1720 1 0 {name=L17
m=1
value=1e10
footprint=1206
device=inductor}
C {devices/vcvs.sym} 2180 -1760 0 0 {name=E8 value=-0.5}
C {devices/gnd.sym} 2120 -1740 0 0 {name=l18 lab=GND}
C {devices/lab_wire.sym} 2120 -1780 0 0 {name=Vac6 sig_type=std_logic lab=vac
value="0 ac 1"}
C {devices/capa.sym} 2250 -1720 3 1 {name=C4
m=1
value=1e-10
footprint=1206
device="ceramic capacitor"}
C {devices/gnd.sym} 2240 -1790 0 0 {name=l19 lab=GND}
C {ldo_ota.sym} 2440 -1360 0 0 {name=x4}
C {devices/lab_wire.sym} 2440 -1540 0 1 {name=p25 sig_type=std_logic lab=VDD}
C {devices/lab_wire.sym} 2440 -1310 2 1 {name=p26 sig_type=std_logic lab=VSS}
C {devices/lab_wire.sym} 2560 -1360 0 1 {name=p27 sig_type=std_logic lab=out_psrr}
C {devices/noconn.sym} 2580 -1360 0 1 {name=l20}
C {devices/capa.sym} 2500 -1490 0 1 {name=C5
m=1
value=1e-10
footprint=1206
device="ceramic capacitor"}
C {devices/vcvs.sym} 2220 -1350 0 0 {name=E10 value=1}
C {devices/gnd.sym} 2220 -1320 0 0 {name=l23 lab=GND}
C {devices/gnd.sym} 2180 -1320 0 0 {name=l24 lab=GND}
C {devices/lab_wire.sym} 2180 -1370 0 0 {name=p28 sig_type=std_logic lab=vcm}
C {devices/ind.sym} 2440 -1490 2 0 {name=L28
m=1
value=1e10
footprint=1206
device=inductor}
C {devices/vcvs.sym} 2600 -1520 0 0 {name=E12 value=1}
C {devices/lab_wire.sym} 2540 -1540 0 0 {name=Vac9 sig_type=std_logic lab=vac
value="0 ac 1"}
C {devices/gnd.sym} 2540 -1500 0 0 {name=l29 lab=GND}
